VERSION 5.7 ;
  NOWIREEXTENSIONATPIN ON ;
  DIVIDERCHAR "/" ;
  BUSBITCHARS "[]" ;
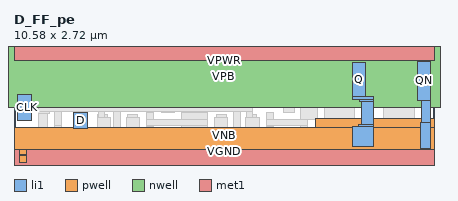
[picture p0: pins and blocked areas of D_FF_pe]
MACRO D_FF_pe
  CLASS CORE ;
  FOREIGN D_FF_pe ;
  ORIGIN 0.000 0.000 ;
  SIZE 10.580 BY 2.720 ;
  PIN CLK
    DIRECTION INPUT ;
    USE CLOCK ;
    ANTENNAGATEAREA 0.159000 ;
    PORT
      LAYER li1 ;
        RECT 0.090 0.975 0.440 1.625 ;
    END
  END CLK
  PIN VNB
    DIRECTION INOUT ;
    USE GROUND ;
    PORT
      LAYER pwell ;
        RECT 7.605 0.785 10.580 1.015 ;
        RECT 0.005 0.240 10.580 0.785 ;
        RECT 0.140 0.105 0.310 0.240 ;
        RECT 7.605 0.235 10.370 0.240 ;
        RECT 0.140 0.085 0.315 0.105 ;
        RECT 0.140 -0.085 0.310 0.085 ;
    END
  END VNB
  PIN VPB
    DIRECTION INOUT ;
    USE POWER ;
    PORT
      LAYER nwell ;
        RECT -0.190 1.305 10.765 2.910 ;
    END
  END VPB
  PIN VPWR
    DIRECTION INOUT ;
    USE POWER ;
    PORT
      LAYER met1 ;
        RECT 0.000 2.480 10.580 2.960 ;
    END
  END VPWR
  PIN VGND
    DIRECTION INOUT ;
    USE GROUND ;
    PORT
      LAYER met1 ;
        RECT 8.900 0.240 9.200 0.245 ;
        RECT 0.000 -0.240 10.580 0.240 ;
    END
  END VGND
  PIN D
    DIRECTION INPUT ;
    USE SIGNAL ;
    ANTENNAGATEAREA 0.159000 ;
    PORT
      LAYER li1 ;
        RECT 1.510 0.760 1.855 1.165 ;
    END
  END D
  PIN Q
    DIRECTION OUTPUT ;
    USE SIGNAL ;
    ANTENNADIFFAREA 0.429000 ;
    PORT
      LAYER li1 ;
        RECT 8.525 1.575 8.855 2.420 ;
        RECT 8.525 1.495 9.055 1.575 ;
        RECT 8.700 1.445 9.055 1.495 ;
        RECT 8.745 0.865 9.055 1.445 ;
        RECT 8.690 0.825 9.055 0.865 ;
        RECT 8.535 0.305 9.055 0.825 ;
    END
  END Q
  PIN QN
    DIRECTION OUTPUT ;
    USE SIGNAL ;
    ANTENNADIFFAREA 0.429000 ;
    PORT
      LAYER li1 ;
        RECT 10.155 1.480 10.490 2.465 ;
        RECT 10.255 0.910 10.490 1.480 ;
        RECT 10.235 0.255 10.490 0.910 ;
    END
  END QN
  OBS
      LAYER li1 ;
        RECT 0.175 1.965 0.345 2.465 ;
        RECT 1.015 1.965 1.200 2.465 ;
        RECT 2.235 2.195 2.685 2.395 ;
        RECT 3.925 2.205 4.380 2.410 ;
        RECT 2.515 2.035 2.685 2.195 ;
        RECT 0.175 1.795 0.840 1.965 ;
        RECT 0.610 0.805 0.840 1.795 ;
        RECT 0.175 0.635 0.840 0.805 ;
        RECT 1.015 1.755 1.205 1.965 ;
        RECT 2.515 1.865 3.875 2.035 ;
        RECT 1.015 0.835 1.200 1.755 ;
        RECT 2.065 1.495 2.345 1.665 ;
        RECT 2.095 1.335 2.345 1.495 ;
        RECT 0.175 0.345 0.345 0.635 ;
        RECT 1.015 0.515 1.205 0.835 ;
        RECT 2.095 0.795 2.345 1.125 ;
        RECT 1.015 0.345 1.200 0.515 ;
        RECT 2.515 0.500 2.685 1.865 ;
        RECT 2.855 1.495 3.135 1.665 ;
        RECT 3.705 1.510 3.875 1.865 ;
        RECT 2.855 1.335 3.105 1.495 ;
        RECT 3.705 1.430 4.035 1.510 ;
        RECT 3.705 1.180 4.040 1.430 ;
        RECT 4.210 1.165 4.380 2.205 ;
        RECT 5.250 2.195 5.700 2.395 ;
        RECT 6.940 2.205 7.395 2.410 ;
        RECT 5.530 2.035 5.700 2.195 ;
        RECT 5.530 1.865 7.050 2.035 ;
        RECT 5.080 1.495 5.360 1.665 ;
        RECT 5.110 1.335 5.360 1.495 ;
        RECT 2.855 0.795 3.105 1.125 ;
        RECT 3.345 1.005 3.525 1.165 ;
        RECT 4.210 1.005 4.870 1.165 ;
        RECT 3.345 0.835 4.870 1.005 ;
        RECT 3.345 0.830 3.525 0.835 ;
        RECT 4.210 0.760 4.870 0.835 ;
        RECT 5.110 0.795 5.360 1.125 ;
        RECT 4.210 0.505 4.380 0.760 ;
        RECT 2.235 0.255 2.685 0.500 ;
        RECT 3.925 0.255 4.380 0.505 ;
        RECT 5.530 0.500 5.700 1.865 ;
        RECT 5.870 1.495 6.150 1.665 ;
        RECT 5.870 1.335 6.120 1.495 ;
        RECT 6.880 1.430 7.050 1.865 ;
        RECT 6.800 1.180 7.055 1.430 ;
        RECT 7.225 1.325 7.395 2.205 ;
        RECT 7.675 1.530 8.015 2.465 ;
        RECT 9.250 1.715 9.580 2.445 ;
        RECT 7.825 1.325 8.015 1.530 ;
        RECT 9.310 1.325 9.580 1.715 ;
        RECT 5.870 0.795 6.120 1.125 ;
        RECT 6.360 1.005 6.540 1.165 ;
        RECT 7.225 1.005 7.655 1.325 ;
        RECT 6.360 0.995 7.655 1.005 ;
        RECT 7.825 0.995 8.575 1.325 ;
        RECT 9.310 0.995 10.085 1.325 ;
        RECT 6.360 0.835 7.395 0.995 ;
        RECT 6.360 0.830 6.540 0.835 ;
        RECT 7.225 0.505 7.395 0.835 ;
        RECT 7.825 0.825 8.025 0.995 ;
        RECT 5.250 0.255 5.700 0.500 ;
        RECT 6.940 0.255 7.395 0.505 ;
        RECT 7.695 0.300 8.025 0.825 ;
        RECT 9.310 0.615 9.510 0.995 ;
        RECT 9.260 0.345 9.510 0.615 ;
      LAYER mcon ;
        RECT 0.670 1.175 0.840 1.345 ;
        RECT 1.035 1.785 1.205 1.955 ;
        RECT 2.065 1.495 2.235 1.665 ;
        RECT 2.175 0.845 2.345 1.015 ;
        RECT 1.035 0.515 1.205 0.685 ;
        RECT 2.965 1.495 3.135 1.665 ;
        RECT 5.080 1.495 5.250 1.665 ;
        RECT 2.935 0.840 3.105 1.010 ;
        RECT 5.110 0.840 5.280 1.010 ;
        RECT 5.980 1.495 6.150 1.665 ;
        RECT 5.950 0.840 6.120 1.010 ;
      LAYER met1 ;
        RECT 0.975 1.855 6.090 1.995 ;
        RECT 0.975 1.755 1.265 1.855 ;
        RECT 2.100 1.695 2.250 1.855 ;
        RECT 5.940 1.695 6.090 1.855 ;
        RECT 2.005 1.465 2.295 1.695 ;
        RECT 2.905 1.465 3.195 1.695 ;
        RECT 5.020 1.465 5.310 1.695 ;
        RECT 5.920 1.465 6.210 1.695 ;
        RECT 0.610 1.325 0.900 1.375 ;
        RECT 3.000 1.325 3.150 1.465 ;
        RECT 5.115 1.325 5.255 1.465 ;
        RECT 0.610 1.185 6.005 1.325 ;
        RECT 0.610 1.145 0.900 1.185 ;
        RECT 2.130 1.045 2.270 1.185 ;
        RECT 5.865 1.045 6.005 1.185 ;
        RECT 2.095 0.800 2.435 1.045 ;
        RECT 2.825 0.800 3.165 1.045 ;
        RECT 5.050 0.800 5.390 1.045 ;
        RECT 5.840 0.800 6.180 1.045 ;
        RECT 0.975 0.520 1.265 0.720 ;
        RECT 2.960 0.520 3.100 0.800 ;
        RECT 5.070 0.520 5.210 0.800 ;
        RECT 0.975 0.380 5.210 0.520 ;
  END
END D_FF_pe
END LIBRARY

